VERSION 5.8 ;
BUSBITCHARS "[]" ;
DIVIDERCHAR "/" ;
UNITS
    DATABASE MICRONS 1000 ;
END UNITS

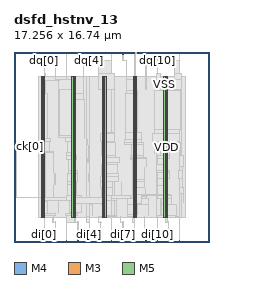
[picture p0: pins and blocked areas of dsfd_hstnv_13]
MACRO dsfd_hstnv_13
  FOREIGN dsfd_hstnv_13 0 0 ;
  CLASS BLOCK ;
  SIZE 17.256 BY 16.74 ;
  PIN ck[0]
    DIRECTION INPUT ;
    USE SIGNAL ;
    PORT
      LAYER M4 ;
        RECT  0 8.4 0.192 8.424 ;
    END
  END ck[0]
  PIN di[0]
    DIRECTION INPUT ;
    USE SIGNAL ;
    PORT
      LAYER M3 ;
        RECT  2.664 0 2.682 0.144 ;
    END
  END di[0]
  PIN di[10]
    DIRECTION INPUT ;
    USE SIGNAL ;
    PORT
      LAYER M3 ;
        RECT  12.6 0 12.618 0.144 ;
    END
  END di[10]
  PIN di[11]
    DIRECTION INPUT ;
    USE SIGNAL ;
    PORT
      LAYER M5 ;
        RECT  13.584 0 13.608 0.192 ;
    END
  END di[11]
  PIN di[12]
    DIRECTION INPUT ;
    USE SIGNAL ;
    PORT
      LAYER M3 ;
        RECT  14.58 0 14.598 0.144 ;
    END
  END di[12]
  PIN di[1]
    DIRECTION INPUT ;
    USE SIGNAL ;
    PORT
      LAYER M5 ;
        RECT  3.648 0 3.672 0.192 ;
    END
  END di[1]
  PIN di[2]
    DIRECTION INPUT ;
    USE SIGNAL ;
    PORT
      LAYER M3 ;
        RECT  4.644 0 4.662 0.144 ;
    END
  END di[2]
  PIN di[3]
    DIRECTION INPUT ;
    USE SIGNAL ;
    PORT
      LAYER M5 ;
        RECT  5.616 0 5.64 0.192 ;
    END
  END di[3]
  PIN di[4]
    DIRECTION INPUT ;
    USE SIGNAL ;
    PORT
      LAYER M3 ;
        RECT  6.624 0 6.642 0.144 ;
    END
  END di[4]
  PIN di[5]
    DIRECTION INPUT ;
    USE SIGNAL ;
    PORT
      LAYER M5 ;
        RECT  7.632 0 7.656 0.192 ;
    END
  END di[5]
  PIN di[6]
    DIRECTION INPUT ;
    USE SIGNAL ;
    PORT
      LAYER M3 ;
        RECT  8.604 0 8.622 0.144 ;
    END
  END di[6]
  PIN di[7]
    DIRECTION INPUT ;
    USE SIGNAL ;
    PORT
      LAYER M5 ;
        RECT  9.6 0 9.624 0.192 ;
    END
  END di[7]
  PIN di[8]
    DIRECTION INPUT ;
    USE SIGNAL ;
    PORT
      LAYER M3 ;
        RECT  10.62 0 10.638 0.144 ;
    END
  END di[8]
  PIN di[9]
    DIRECTION INPUT ;
    USE SIGNAL ;
    PORT
      LAYER M5 ;
        RECT  11.616 0 11.64 0.192 ;
    END
  END di[9]
  PIN dq[0]
    DIRECTION OUTPUT ;
    USE SIGNAL ;
    PORT
      LAYER M3 ;
        RECT  2.664 16.596 2.682 16.74 ;
    END
  END dq[0]
  PIN dq[10]
    DIRECTION OUTPUT ;
    USE SIGNAL ;
    PORT
      LAYER M3 ;
        RECT  12.6 16.596 12.618 16.74 ;
    END
  END dq[10]
  PIN dq[11]
    DIRECTION OUTPUT ;
    USE SIGNAL ;
    PORT
      LAYER M5 ;
        RECT  13.584 16.548 13.608 16.74 ;
    END
  END dq[11]
  PIN dq[12]
    DIRECTION OUTPUT ;
    USE SIGNAL ;
    PORT
      LAYER M3 ;
        RECT  14.58 16.596 14.598 16.74 ;
    END
  END dq[12]
  PIN dq[1]
    DIRECTION OUTPUT ;
    USE SIGNAL ;
    PORT
      LAYER M5 ;
        RECT  3.648 16.548 3.672 16.74 ;
    END
  END dq[1]
  PIN dq[2]
    DIRECTION OUTPUT ;
    USE SIGNAL ;
    PORT
      LAYER M3 ;
        RECT  4.644 16.596 4.662 16.74 ;
    END
  END dq[2]
  PIN dq[3]
    DIRECTION OUTPUT ;
    USE SIGNAL ;
    PORT
      LAYER M5 ;
        RECT  5.616 16.548 5.64 16.74 ;
    END
  END dq[3]
  PIN dq[4]
    DIRECTION OUTPUT ;
    USE SIGNAL ;
    PORT
      LAYER M3 ;
        RECT  6.624 16.596 6.642 16.74 ;
    END
  END dq[4]
  PIN dq[5]
    DIRECTION OUTPUT ;
    USE SIGNAL ;
    PORT
      LAYER M5 ;
        RECT  7.632 16.548 7.656 16.74 ;
    END
  END dq[5]
  PIN dq[6]
    DIRECTION OUTPUT ;
    USE SIGNAL ;
    PORT
      LAYER M3 ;
        RECT  8.604 16.596 8.622 16.74 ;
    END
  END dq[6]
  PIN dq[7]
    DIRECTION OUTPUT ;
    USE SIGNAL ;
    PORT
      LAYER M5 ;
        RECT  9.6 16.548 9.624 16.74 ;
    END
  END dq[7]
  PIN dq[8]
    DIRECTION OUTPUT ;
    USE SIGNAL ;
    PORT
      LAYER M3 ;
        RECT  10.62 16.596 10.638 16.74 ;
    END
  END dq[8]
  PIN dq[9]
    DIRECTION OUTPUT ;
    USE SIGNAL ;
    PORT
      LAYER M5 ;
        RECT  11.616 16.548 11.64 16.74 ;
    END
  END dq[9]
  PIN VDD
    DIRECTION INOUT ;
    USE POWER ;
    PORT
      LAYER M5 ;
        RECT  13.392 2.151 13.512 14.589 ;
        RECT  10.692 2.151 10.812 14.589 ;
        RECT  7.992 2.151 8.112 14.589 ;
        RECT  5.292 2.151 5.412 14.589 ;
        RECT  2.592 2.151 2.712 14.589 ;
    END
  END VDD
  PIN VSS
    DIRECTION INOUT ;
    USE GROUND ;
    PORT
      LAYER M5 ;
        RECT  13.2 2.137 13.32 14.603 ;
        RECT  10.5 2.137 10.62 14.603 ;
        RECT  7.8 2.137 7.92 14.603 ;
        RECT  5.1 2.137 5.22 14.603 ;
        RECT  2.4 2.137 2.52 14.603 ;
    END
  END VSS
  OBS
    LAYER RVTN ;
     RECT  2.16 2.16 15.066 2.295 ;
     RECT  2.16 2.565 15.066 2.835 ;
     RECT  2.16 3.105 15.066 3.375 ;
     RECT  2.16 3.645 15.066 3.915 ;
     RECT  2.16 4.185 15.066 4.455 ;
     RECT  2.16 4.725 15.066 4.995 ;
     RECT  2.16 5.265 15.066 5.535 ;
     RECT  2.16 5.805 15.066 6.075 ;
     RECT  2.16 6.345 15.066 6.615 ;
     RECT  2.16 6.885 15.066 7.155 ;
     RECT  2.16 7.425 15.066 7.695 ;
     RECT  2.16 7.965 15.066 8.235 ;
     RECT  2.16 8.505 15.066 8.775 ;
     RECT  2.16 9.045 15.066 9.315 ;
     RECT  2.16 9.585 15.066 9.855 ;
     RECT  2.16 10.125 15.066 10.395 ;
     RECT  2.16 10.665 15.066 10.935 ;
     RECT  2.16 11.205 15.066 11.475 ;
     RECT  2.16 11.745 15.066 12.015 ;
     RECT  2.16 12.285 15.066 12.555 ;
     RECT  2.16 12.825 15.066 13.095 ;
     RECT  2.16 13.365 15.066 13.635 ;
     RECT  2.16 13.905 15.066 14.175 ;
     RECT  2.16 14.445 15.066 14.58 ;
    LAYER RVTP ;
     RECT  2.16 2.295 15.066 2.565 ;
     RECT  2.16 2.835 15.066 3.105 ;
     RECT  2.16 3.375 15.066 3.645 ;
     RECT  2.16 3.915 15.066 4.185 ;
     RECT  2.16 4.455 15.066 4.725 ;
     RECT  2.16 4.995 15.066 5.265 ;
     RECT  2.16 5.535 15.066 5.805 ;
     RECT  2.16 6.075 15.066 6.345 ;
     RECT  2.16 6.615 15.066 6.885 ;
     RECT  2.16 7.155 15.066 7.425 ;
     RECT  2.16 7.695 15.066 7.965 ;
     RECT  2.16 8.235 15.066 8.505 ;
     RECT  2.16 8.775 15.066 9.045 ;
     RECT  2.16 9.315 15.066 9.585 ;
     RECT  2.16 9.855 15.066 10.125 ;
     RECT  2.16 10.395 15.066 10.665 ;
     RECT  2.16 10.935 15.066 11.205 ;
     RECT  2.16 11.475 15.066 11.745 ;
     RECT  2.16 12.015 15.066 12.285 ;
     RECT  2.16 12.555 15.066 12.825 ;
     RECT  2.16 13.095 15.066 13.365 ;
     RECT  2.16 13.635 15.066 13.905 ;
     RECT  2.16 14.175 15.066 14.445 ;
    LAYER M1 ;
     RECT  2.16 2.151 15.066 14.589 ;
    LAYER M2 ;
     RECT  2.16 2.151 2.659 14.589 ;
     RECT  2.659 2.151 2.759 14.859 ;
     RECT  2.759 2.151 6.403 14.589 ;
     RECT  6.403 1.728 6.647 14.589 ;
     RECT  6.619 15.966 7.439 15.984 ;
     RECT  6.647 2.151 8.599 14.589 ;
     RECT  8.599 2.151 8.843 14.859 ;
     RECT  8.843 2.151 10.399 14.589 ;
     RECT  10.399 1.728 10.643 14.589 ;
     RECT  10.615 16.578 10.651 16.596 ;
     RECT  10.651 16.578 10.751 16.668 ;
     RECT  10.643 2.151 12.595 14.589 ;
     RECT  12.595 2.151 12.947 14.859 ;
     RECT  12.947 2.151 14.575 14.589 ;
     RECT  14.575 2.151 14.747 14.859 ;
     RECT  14.747 2.151 15.066 14.589 ;
    LAYER M3 ;
     RECT  4.644 0.108 4.662 1.723 ;
     RECT  6.624 0.108 6.642 1.723 ;
     RECT  10.62 0.108 10.638 1.723 ;
     RECT  2.664 0.108 2.682 2.143 ;
     RECT  7.416 1.723 7.434 2.143 ;
     RECT  8.604 0.108 8.622 2.143 ;
     RECT  12.6 0.108 12.618 2.143 ;
     RECT  13.356 1.723 13.374 2.143 ;
     RECT  2.415 2.143 2.682 2.191 ;
     RECT  3.42 1.723 3.438 2.191 ;
     RECT  14.58 0.108 14.598 2.191 ;
     RECT  6.408 1.723 6.642 2.255 ;
     RECT  7.416 2.143 8.622 2.255 ;
     RECT  9.36 1.723 9.378 2.255 ;
     RECT  11.484 0.571 11.502 2.255 ;
     RECT  14.256 2.191 14.598 2.255 ;
     RECT  7.815 2.255 8.622 2.263 ;
     RECT  10.404 1.723 10.638 2.263 ;
     RECT  7.815 2.263 9.054 2.291 ;
     RECT  12.6 2.143 13.374 2.291 ;
     RECT  2.415 2.191 3.438 2.371 ;
     RECT  4.644 1.723 5.382 2.371 ;
     RECT  13.032 2.291 13.374 2.371 ;
     RECT  14.256 2.255 14.274 2.371 ;
     RECT  10.008 2.263 10.638 2.413 ;
     RECT  2.415 2.371 3.618 2.489 ;
     RECT  4.572 2.371 5.562 2.489 ;
     RECT  4.932 2.489 5.562 2.641 ;
     RECT  7.815 2.291 8.154 3.271 ;
     RECT  10.008 2.413 10.89 3.271 ;
     RECT  11.808 2.371 11.826 3.271 ;
     RECT  6.876 2.371 6.894 3.299 ;
     RECT  13.032 2.371 14.274 3.299 ;
     RECT  6.732 3.307 6.858 3.437 ;
     RECT  2.415 2.489 2.934 3.569 ;
     RECT  3.924 2.641 3.942 3.569 ;
     RECT  7.668 3.271 8.154 3.643 ;
     RECT  9.036 2.291 9.054 3.643 ;
     RECT  3.744 3.685 3.762 3.721 ;
     RECT  4.932 2.641 5.922 3.721 ;
     RECT  3.492 3.721 3.762 3.725 ;
     RECT  2.415 3.569 2.718 3.749 ;
     RECT  6.84 3.437 6.858 3.773 ;
     RECT  10.008 3.271 11.826 3.839 ;
     RECT  13.032 3.299 13.914 3.847 ;
     RECT  10.008 3.839 11.646 3.965 ;
     RECT  4.716 3.721 5.922 4.075 ;
     RECT  7.668 3.643 9.054 4.075 ;
     RECT  10.008 3.965 10.797 4.075 ;
     RECT  4.644 4.075 5.922 4.109 ;
     RECT  7.668 4.075 10.797 4.109 ;
     RECT  12.6 3.847 13.914 4.109 ;
     RECT  4.644 4.109 5.49 4.115 ;
     RECT  9.432 4.109 9.738 4.115 ;
     RECT  11.592 3.965 11.646 4.157 ;
     RECT  12.6 4.109 13.734 4.157 ;
     RECT  14.904 3.451 14.922 4.261 ;
     RECT  11.592 4.157 11.61 4.685 ;
     RECT  14.616 4.261 14.922 4.793 ;
     RECT  7.668 4.109 8.694 4.801 ;
     RECT  10.515 4.109 10.797 4.801 ;
     RECT  3.492 3.725 3.51 4.955 ;
     RECT  12.6 4.157 13.554 4.955 ;
     RECT  4.716 4.115 5.49 5.071 ;
     RECT  6.624 4.261 6.642 5.225 ;
     RECT  9.432 4.115 9.45 5.225 ;
     RECT  4.68 5.071 5.49 5.341 ;
     RECT  7.632 4.801 8.694 5.341 ;
     RECT  10.515 4.801 11.502 5.341 ;
     RECT  10.44 5.341 11.502 5.495 ;
     RECT  12.672 4.955 13.554 5.611 ;
     RECT  14.616 4.793 14.85 5.611 ;
     RECT  7.632 5.341 9.234 5.765 ;
     RECT  3.6 5.071 3.618 6.035 ;
     RECT  4.68 5.341 5.634 6.035 ;
     RECT  6.552 5.341 6.57 6.035 ;
     RECT  7.74 5.765 9.234 6.035 ;
     RECT  10.44 5.495 10.797 6.035 ;
     RECT  12.672 5.611 13.662 6.151 ;
     RECT  4.788 6.035 5.634 6.305 ;
     RECT  12.564 6.151 13.662 6.305 ;
     RECT  14.508 5.611 14.85 6.305 ;
     RECT  11.52 5.611 11.538 6.575 ;
     RECT  14.616 6.305 14.85 6.691 ;
     RECT  6.624 6.151 6.642 6.845 ;
     RECT  7.74 6.035 9.162 6.845 ;
     RECT  12.564 6.305 13.554 6.845 ;
     RECT  7.815 6.845 9.162 6.961 ;
     RECT  4.788 6.305 5.454 7.231 ;
     RECT  10.476 6.035 10.797 7.231 ;
     RECT  10.296 7.231 10.797 7.321 ;
     RECT  11.664 6.691 11.682 7.321 ;
     RECT  6.444 6.961 6.57 7.349 ;
     RECT  12.636 6.845 13.554 7.393 ;
     RECT  7.815 6.961 9.306 7.421 ;
     RECT  10.296 7.321 11.682 7.421 ;
     RECT  7.815 7.421 8.946 7.591 ;
     RECT  10.296 7.421 11.43 7.619 ;
     RECT  12.636 7.393 13.698 7.619 ;
     RECT  14.616 6.691 14.922 7.619 ;
     RECT  4.608 7.231 5.526 7.655 ;
     RECT  2.415 3.749 2.697 7.861 ;
     RECT  3.456 6.151 3.474 7.861 ;
     RECT  4.608 7.655 5.397 7.889 ;
     RECT  2.415 7.861 3.474 7.961 ;
     RECT  14.616 7.619 14.706 8.159 ;
     RECT  13.176 7.619 13.698 8.311 ;
     RECT  14.616 8.159 14.634 8.311 ;
     RECT  6.552 7.349 6.57 8.465 ;
     RECT  10.368 7.619 11.43 8.581 ;
     RECT  13.176 8.311 14.634 8.735 ;
     RECT  7.704 7.591 8.946 8.771 ;
     RECT  9.72 8.581 11.43 8.771 ;
     RECT  2.415 7.961 3.15 8.851 ;
     RECT  4.716 7.889 5.397 8.851 ;
     RECT  7.704 8.771 8.874 8.851 ;
     RECT  12.348 7.771 12.366 8.851 ;
     RECT  13.176 8.735 14.598 8.851 ;
     RECT  9.72 8.771 11.25 9.005 ;
     RECT  6.48 8.581 6.498 9.041 ;
     RECT  2.415 8.851 3.222 9.113 ;
     RECT  4.572 8.851 5.397 9.211 ;
     RECT  3.96 9.211 5.397 9.383 ;
     RECT  7.632 8.851 8.874 9.545 ;
     RECT  12.24 8.851 14.598 9.545 ;
     RECT  7.776 9.545 8.874 9.653 ;
     RECT  9.792 9.005 11.25 9.653 ;
     RECT  12.348 9.545 14.598 9.931 ;
     RECT  5.076 9.383 5.397 12.559 ;
     RECT  6.228 9.085 6.246 12.559 ;
     RECT  5.076 12.559 6.246 12.587 ;
     RECT  2.415 9.113 2.97 13.055 ;
     RECT  5.076 12.587 6.138 13.055 ;
     RECT  9.792 9.653 10.854 13.055 ;
     RECT  9.9 13.055 10.854 13.325 ;
     RECT  12.348 9.931 14.67 13.325 ;
     RECT  3.96 9.383 3.978 13.441 ;
     RECT  5.076 13.055 5.397 13.441 ;
     RECT  7.776 9.653 8.586 13.441 ;
     RECT  12.924 13.325 14.67 13.441 ;
     RECT  3.96 13.441 5.397 14.285 ;
     RECT  4.644 14.285 5.397 14.327 ;
     RECT  9.9 13.325 10.797 14.327 ;
     RECT  12.924 13.441 14.742 14.327 ;
     RECT  2.415 13.055 2.754 14.597 ;
     RECT  4.644 14.327 5.205 14.597 ;
     RECT  9.9 14.327 10.674 14.597 ;
     RECT  12.924 14.327 13.305 14.597 ;
     RECT  11.628 13.441 11.646 14.813 ;
     RECT  12.924 14.597 12.942 14.836 ;
     RECT  2.664 14.597 2.754 14.864 ;
     RECT  7.416 13.441 8.838 14.864 ;
     RECT  12.6 14.836 12.942 14.864 ;
     RECT  14.112 14.327 14.742 14.864 ;
     RECT  6.12 13.055 6.138 15.961 ;
     RECT  7.416 14.864 8.622 15.989 ;
     RECT  6.12 15.961 6.642 16.013 ;
     RECT  8.136 15.989 8.622 16.013 ;
     RECT  9.9 14.597 9.918 16.013 ;
     RECT  14.112 14.864 14.598 16.013 ;
     RECT  10.656 14.597 10.674 16.573 ;
     RECT  2.664 14.864 2.682 16.62 ;
     RECT  4.644 14.597 4.662 16.62 ;
     RECT  6.624 16.013 6.642 16.62 ;
     RECT  8.604 16.013 8.622 16.62 ;
     RECT  10.62 16.573 10.746 16.62 ;
     RECT  12.6 14.864 12.618 16.62 ;
     RECT  14.58 16.013 14.598 16.62 ;
     RECT  10.656 16.62 10.746 16.673 ;
    LAYER M4 ;
     RECT  0.156 8.4 0.275 8.424 ;
     RECT  0.229 3.888 2.408 3.912 ;
     RECT  2.408 2.148 2.512 14.592 ;
     RECT  2.512 2.148 2.704 14.322 ;
     RECT  3.409 1.728 3.683 1.752 ;
     RECT  2.704 14.256 3.989 14.28 ;
     RECT  2.704 3.696 4.597 3.912 ;
     RECT  4.597 3.696 5.108 4.104 ;
     RECT  5.108 2.148 5.212 14.592 ;
     RECT  5.212 2.148 5.353 14.322 ;
     RECT  5.353 1.728 5.404 14.322 ;
     RECT  5.404 1.728 5.651 1.752 ;
     RECT  5.605 15.984 6.149 16.008 ;
     RECT  7.405 1.728 7.667 1.752 ;
     RECT  5.404 3.408 7.808 3.912 ;
     RECT  7.808 2.148 7.912 14.592 ;
     RECT  7.912 2.418 8.104 14.322 ;
     RECT  7.621 15.984 8.165 16.008 ;
     RECT  8.104 3.648 8.561 4.104 ;
     RECT  9.349 1.728 9.635 1.752 ;
     RECT  9.589 15.984 9.929 16.008 ;
     RECT  8.561 3.84 10.508 4.104 ;
     RECT  10.508 2.148 10.612 14.592 ;
     RECT  10.612 2.418 10.804 14.322 ;
     RECT  10.804 3.408 11.261 4.152 ;
     RECT  11.473 0.576 11.651 0.6 ;
     RECT  11.573 14.784 11.657 14.808 ;
     RECT  11.261 4.128 13.208 4.152 ;
     RECT  13.208 2.148 13.312 14.592 ;
     RECT  13.312 2.148 13.345 14.322 ;
     RECT  13.345 1.728 13.504 14.322 ;
     RECT  13.504 1.728 13.619 1.752 ;
     RECT  13.504 4.128 13.745 4.152 ;
     RECT  13.573 15.984 14.141 16.008 ;
    LAYER M5 ;
     RECT  11.616 0.144 11.64 0.611 ;
     RECT  3.648 0.144 3.672 1.763 ;
     RECT  5.616 0.144 5.64 1.763 ;
     RECT  7.632 0.144 7.656 1.763 ;
     RECT  9.6 0.144 9.624 1.763 ;
     RECT  13.584 0.144 13.608 1.763 ;
     RECT  2.4 2.137 2.52 2.151 ;
     RECT  7.8 2.137 7.92 2.151 ;
     RECT  10.5 2.137 10.62 2.151 ;
     RECT  5.1 2.137 5.412 3.685 ;
     RECT  10.5 2.151 10.812 3.925 ;
     RECT  4.608 3.685 5.412 4.115 ;
     RECT  10.272 3.925 10.812 4.115 ;
     RECT  0.24 3.877 0.264 8.435 ;
     RECT  2.4 2.151 2.712 14.245 ;
     RECT  2.4 14.245 3.672 14.589 ;
     RECT  5.1 4.115 5.412 14.589 ;
     RECT  7.8 2.151 8.112 14.589 ;
     RECT  10.5 4.115 10.812 14.589 ;
     RECT  13.2 2.137 13.512 14.589 ;
     RECT  2.4 14.589 2.52 14.603 ;
     RECT  5.1 14.589 5.22 14.603 ;
     RECT  7.8 14.589 7.92 14.603 ;
     RECT  10.5 14.589 10.62 14.603 ;
     RECT  13.2 14.589 13.32 14.603 ;
     RECT  3.648 14.589 3.672 16.592 ;
     RECT  5.616 15.973 5.64 16.592 ;
     RECT  7.632 15.973 7.656 16.592 ;
     RECT  9.6 15.973 9.624 16.592 ;
     RECT  11.616 14.773 11.64 16.592 ;
     RECT  13.584 15.973 13.608 16.592 ;
  END
END dsfd_hstnv_13
END LIBRARY
